One B-rep face of a CAD part: STEP entity #333.
In plain terms, the planar face has unit normal (1, 0, 0).
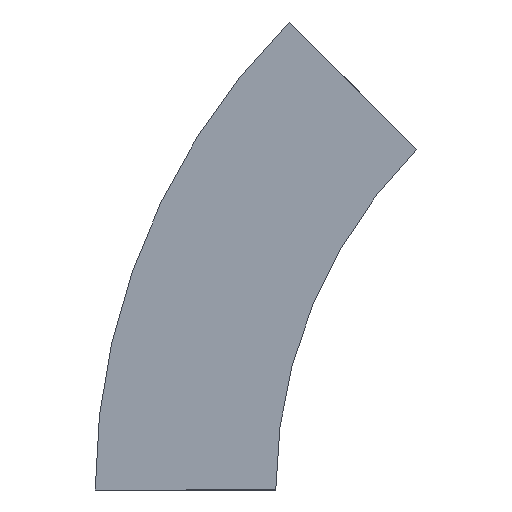
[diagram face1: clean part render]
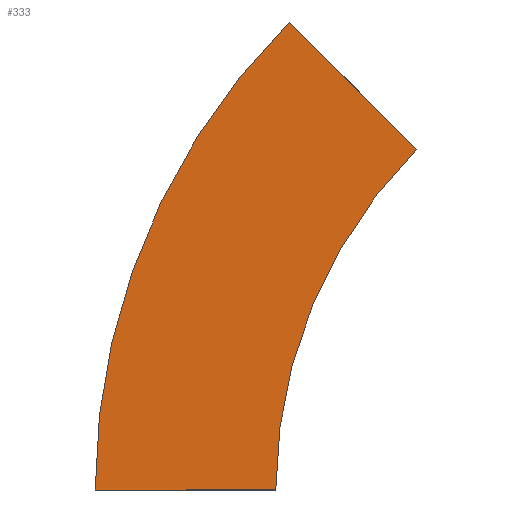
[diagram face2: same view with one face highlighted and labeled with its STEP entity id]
Its self-contained STEP definition (entity closure, numbers rounded to 3 decimals):
#9 = CARTESIAN_POINT ( 'NONE',  ( 0., -87.868, 212.132 ) ) ;
#11 = VERTEX_POINT ( 'NONE', #415 ) ;
#27 = PLANE ( 'NONE',  #390 ) ;
#30 = LINE ( 'NONE', #203, #275 ) ;
#35 = ORIENTED_EDGE ( 'NONE', *, *, #483, .F. ) ;
#65 = VERTEX_POINT ( 'NONE', #508 ) ;
#134 = DIRECTION ( 'NONE',  ( 1., 0., 0. ) ) ;
#137 = CIRCLE ( 'NONE', #213, 300. ) ;
#141 = DIRECTION ( 'NONE',  ( 1., 0., 0. ) ) ;
#198 = CARTESIAN_POINT ( 'NONE',  ( 0., -300., 0. ) ) ;
#200 = VERTEX_POINT ( 'NONE', #432 ) ;
#203 = CARTESIAN_POINT ( 'NONE',  ( 0., 0., 0. ) ) ;
#210 = ORIENTED_EDGE ( 'NONE', *, *, #348, .T. ) ;
#213 = AXIS2_PLACEMENT_3D ( 'NONE', #198, #556, #290 ) ;
#260 = VECTOR ( 'NONE', #352, 1000. ) ;
#270 = CARTESIAN_POINT ( 'NONE',  ( 0., 0., 0. ) ) ;
#275 = VECTOR ( 'NONE', #564, 1000. ) ;
#287 = AXIS2_PLACEMENT_3D ( 'NONE', #531, #134, #444 ) ;
#290 = DIRECTION ( 'NONE',  ( 0., 1., 0. ) ) ;
#294 = EDGE_LOOP ( 'NONE', ( #210, #389, #35, #392 ) ) ;
#322 = EDGE_CURVE ( 'NONE', #65, #11, #30, .T. ) ;
#333 = ADVANCED_FACE ( 'NONE', ( #555 ), #27, .T. ) ;
#348 = EDGE_CURVE ( 'NONE', #11, #467, #482, .T. ) ;
#352 = DIRECTION ( 'NONE',  ( 0., 0.707, 0.707 ) ) ;
#355 = EDGE_CURVE ( 'NONE', #200, #467, #403, .T. ) ;
#389 = ORIENTED_EDGE ( 'NONE', *, *, #355, .F. ) ;
#390 = AXIS2_PLACEMENT_3D ( 'NONE', #270, #141, #441 ) ;
#392 = ORIENTED_EDGE ( 'NONE', *, *, #322, .T. ) ;
#403 = LINE ( 'NONE', #9, #260 ) ;
#415 = CARTESIAN_POINT ( 'NONE',  ( 0., 112.5, 0. ) ) ;
#432 = CARTESIAN_POINT ( 'NONE',  ( 0., -87.868, 212.132 ) ) ;
#441 = DIRECTION ( 'NONE',  ( 0., 0., -1. ) ) ;
#444 = DIRECTION ( 'NONE',  ( 0., 1., 0. ) ) ;
#467 = VERTEX_POINT ( 'NONE', #507 ) ;
#482 = CIRCLE ( 'NONE', #287, 412.5 ) ;
#483 = EDGE_CURVE ( 'NONE', #65, #200, #137, .T. ) ;
#507 = CARTESIAN_POINT ( 'NONE',  ( 0., -8.318, 291.682 ) ) ;
#508 = CARTESIAN_POINT ( 'NONE',  ( 0., 0., 0. ) ) ;
#531 = CARTESIAN_POINT ( 'NONE',  ( 0., -300., 0. ) ) ;
#555 = FACE_OUTER_BOUND ( 'NONE', #294, .T. ) ;
#556 = DIRECTION ( 'NONE',  ( 1., 0., 0. ) ) ;
#564 = DIRECTION ( 'NONE',  ( 0., 1., 0. ) ) ;
